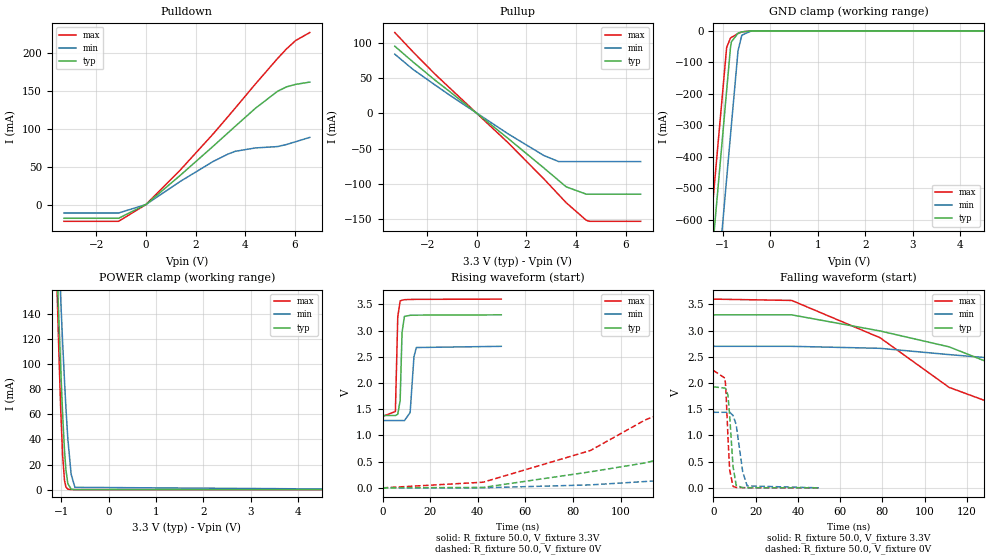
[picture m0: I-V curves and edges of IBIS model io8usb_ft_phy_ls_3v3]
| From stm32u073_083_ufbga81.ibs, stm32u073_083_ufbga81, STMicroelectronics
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[Model]   io8usb_ft_phy_ls_3v3
Model_type I/O
Polarity   Inverting
Enable   Active-Low
| CAP_THRESHOLD on pad DNFT is "UDTCAPC" :
| Rising=30.0% of vddiom   Falling=70.0% of vddiom
| C_comp min and max val. don't necessarily correlate with the min and max pvt
| but are the smallest and greatest pad capacitance found.
| var   typ   min   max
C_comp   8.83670pF  8.38806pF  11.45830pF
|C_comp_pullup   5.20650pF  4.52075pF  7.78905pF
|C_comp_pulldown   3.63020pF  3.86731pF  3.66925pF
Vinl = 810.0mV
Vinh = 2.52V
Vmeas = 1.65V   | Reference voltage for timing measurements
Cref  = 0F   | Timing specification test load capacitance value
Rref  = 100.0MOhm   | Timing specification test load resistance value
Vref  = 1.65V   | Timing specification test load voltage
[Model Spec]
| TIME_THRESHOLD on pin ZINV12 is "CMOS" :
| Rising=50.0% of vdd   Falling=50.0% of vdd
Vinl 1.34770V 1.11470V 1.44970V
Vinh 1.77530V 1.49030V 1.90330V
| variable   typ   min   max
[Temperature Range] 25.0 140.0 -40.0
| variable   typ   min   max
[Voltage Range] 3.3V 2.7V 3.6V
| variable   typ   min   max
[POWER Clamp Reference] 3.3V 2.7V 3.6V
| variable   typ   min   max
[GND Clamp Reference] 0V 0V 0V
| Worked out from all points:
|   slope of the pulldown table from 0 to 0.495 V, typ, clamps not added: 36.1 ohm
|   slope of the pullup table from 0 to 0.495 V, typ, clamps not added: 35.7 ohm
|   GND clamp passes 1 mA (typ) near -0.52 V on its own axis
|   POWER clamp passes 1 mA (typ) near -0.81 V on its own axis
|   rising waveform, R_fixture 50.0, V_fixture 3.3V: 20-80 % time 683ps typ, 1.12ns min, 579ps max; typ from 1.38 V to 3.3 V
|   falling waveform, R_fixture 50.0, V_fixture 3.3V: 20-80 % time 86ns typ, 163ns min, 57.1ns max; typ from 3.3 V to 1.38 V
|   rising waveform, R_fixture 50.0, V_fixture 0V: 20-80 % time 101ns typ, 204ns min, 66.9ns max; typ from 0 V to 1.93 V
|   falling waveform, R_fixture 50.0, V_fixture 0V: 20-80 % time 1.9ns typ, 2.98ns min, 1.51ns max; typ from 1.93 V to 0.001 V
[POWER Clamp]
-3.3V     2.991A     2.546A     3.694A
-1.11V    202.2mA    242.3mA    190.9mA
-1.09V    180mA      223.6mA    163.4mA
-1.05V    136.9mA    187mA      110.9mA
-1.01V    96.55mA    151.6mA    64.02mA
-970mV    60.39mA    117.9mA    27.41mA
-930mV    31.08mA    86.54mA    7.282mA
-900mV    15.67mA    65.13mA    2.025mA
-860mV    4.779mA    40.5mA     315.2uA
-790mV    394.2uA    12.22mA    11.25uA
-710mV    19.95uA    1.811mA    247.1nA
6.6V      0A         0A         0A
[GND Clamp]
-3.3V     -4.235A    -4.516A    -4.096A
-1.39V    -988.3mA   -1.268A    -848.9mA
-1.24V    -733.3mA   -1.014A    -593.9mA
-1.23V    -716.3mA   -996.5mA   -576.9mA
-1.1V     -495.3mA   -775.5mA   -355.9mA
-920mV    -189.3mA   -469.5mA   -53.02mA
-840mV    -54.5mA    -333.5mA   -23.28mA
-820mV    -35.01mA   -299.5mA   -20.98mA
-680mV    -7.53mA    -63.11mA   -8.471mA
-600mV    -3.376mA   -13.82mA   -3.494mA
-400mV    -43.64uA   -366.2uA   -14.84uA
6.6V      2.843nA    1.369uA    2.06nA
| variable   typ   min   max
[Pullup Reference] 3.3V 2.7V 3.6V
| variable   typ   min   max
[Pulldown Reference] 0V 0V 0V
[Pullup]
-3.3V     95.3mA     84mA       114.7mA
-2.58V    73.4mA     62.8mA     87.8mA
-1.7V     47.78mA    40.88mA    56.4mA
-1.1V     31.32mA    26.19mA    36.51mA
1.26V     -35.34mA   -28.86mA   -41.44mA
2.7V      -77.2mA    -59.59mA   -92.67mA
3.3V      -95.05mA   -68.22mA   -115.2mA
3.6V      -104mA     -68.22mA   -126.5mA
4.41V     -114.4mA   -68.22mA   -151.4mA
4.53V     -114.4mA   -68.22mA   -152.9mA
6.6V      -114.4mA   -68.22mA   -152.9mA
[Pulldown]
-3.3V     -18.08mA   -11.15mA   -22.07mA
-1.1V     -18.08mA   -11.15mA   -22.07mA
0V        431.7pA    53.17nA    569.2pA
1.38V     38.37mA    30.35mA    45.33mA
2.7V      76.5mA     56.57mA    92.67mA
3.31V     94.54mA    66.48mA    115.9mA
3.6V      103.1mA    70.09mA    127.1mA
4.41V     126.7mA    74.52mA    158.7mA
5.3V      149.1mA    76.3mA     192.2mA
5.66V     154.9mA    79mA       204.8mA
6.03V     158.2mA    82.7mA     215.9mA
6.6V      161.2mA    88.4mA     226.4mA
[Ramp]
dV/dt_r 1.15643V/99.05322ns 864.90818mV/195.52884ns 1.34448V/65.31321ns
dV/dt_f 1.15176V/83.79515ns 849.58363mV/160.14336ns 1.34245V/55.96383ns
R_load = 50.0
| Removed startup time: 0s 0s 0s  .
| Removed end time: 49.9ns.
[Rising Waveform]
R_fixture   = 50.0
V_fixture   = 3.3V
V_fixture_min = 2.7V
V_fixture_max = 3.6V
0s        1.38V      1.284V     1.363V
5.4ns     1.38V      1.284V     1.455V
6.4ns     1.403V     1.284V     3.26V
7.4ns     1.667V     1.284V     3.566V
8.2ns     2.964V     1.284V     3.579V
9.2ns     3.269V     1.283V     3.588V
11.6ns    3.291V     1.437V     3.593V
13.2ns    3.293V     2.499V     3.594V
14.2ns    3.294V     2.676V     3.595V
49.9ns    3.299V     2.699V     3.599V
| Removed startup time: 0s 0s 0s  .
| Removed end time: 999.9ns.
[Falling Waveform]
R_fixture   = 50.0
V_fixture   = 3.3V
V_fixture_min = 2.7V
V_fixture_max = 3.6V
0s        3.3V       2.7V       3.6V
37.1ns    3.3V       2.7V       3.575V
78.9ns    2.993V     2.662V     2.864V
111.6ns   2.69V      2.542V     1.917V
136.2ns   2.299V     2.461V     1.552V
165.3ns   1.829V     2.359V     1.388V
237.1ns   1.418V     1.995V     1.363V
333.3ns   1.381V     1.474V     1.363V
444.4ns   1.38V      1.301V     1.363V
999.9ns   1.38V      1.284V     1.363V
| Removed startup time: 0s 0s 0s  .
| Removed end time: 999.9ns.
[Rising Waveform]
R_fixture   = 50.0
V_fixture   = 0V
V_fixture_min = 0V
V_fixture_max = 0V
0s        84.75nV    591nV      53.04nV
42.3ns    8.46mV     1.182mV    107.9mV
87.4ns    306.3mV    56.56mV    713.3mV
110.1ns   474.4mV    120.1mV    1.289V
144.7ns   848.2mV    215.8mV    1.929V
192.5ns   1.499V     356.1mV    2.215V
276.9ns   1.888V     718mV      2.241V
348.5ns   1.926V     1.08V      2.241V
444.4ns   1.927V     1.338V     2.241V
999.9ns   1.927V     1.442V     2.241V
| Removed startup time: 0s 0s 0s  .
| Removed end time: 49.9ns.
[Falling Waveform]
R_fixture   = 50.0
V_fixture   = 0V
V_fixture_min = 0V
V_fixture_max = 0V
0s        1.927V     1.442V     2.241V
5.5ns     1.904V     1.442V     2.093V
5.9ns     1.883V     1.442V     1.901V
6.9ns     1.77V      1.443V     973.2mV
7.7ns     1.39V      1.443V     350.3mV
9.3ns     412.7mV    1.383V     28.97mV
10.8ns    48.64mV    1.206V     8.165mV
13.9ns    5.159mV    305.4mV    4.551mV
16ns      3.837mV    38.03mV    3.809mV
49.9ns    1.105mV    1.75mV     1.384mV
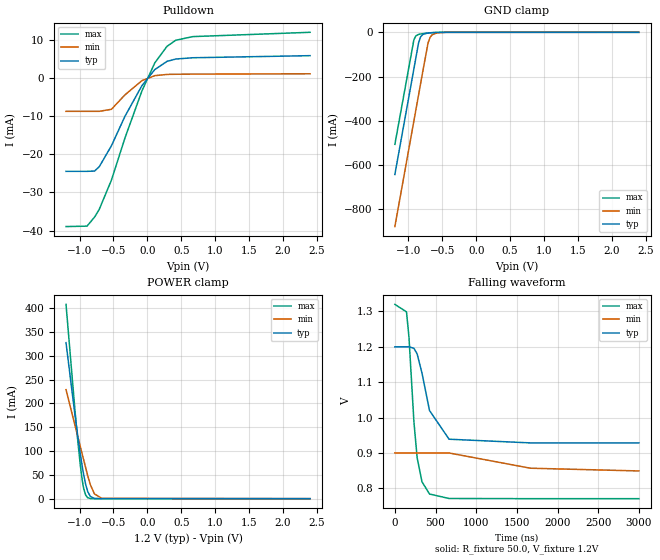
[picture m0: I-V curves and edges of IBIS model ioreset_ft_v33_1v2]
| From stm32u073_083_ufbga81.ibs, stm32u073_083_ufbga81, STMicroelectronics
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[Model]   ioreset_ft_v33_1v2
Model_type I/O_open_drain
Polarity   Inverting
Enable   Active-Low
| CAP_THRESHOLD on pad IOFT is "UDTCAPC" :
| Rising=30.0% of vddiom   Falling=70.0% of vddiom
| C_comp min and max val. don't necessarily correlate with the min and max pvt
| but are the smallest and greatest pad capacitance found.
| var   typ   min   max
C_comp   1.54805pF  1.41325pF  1.57330pF
|C_comp_pulldown   1.54805pF  1.41325pF  1.57330pF
Vinl = 450.0mV
Vinh = 660.0mV
Vmeas = 600.0mV   | Reference voltage for timing measurements
Cref  = 50.0pF   | Timing specification test load capacitance value
Rref  = 1.0MOhm   | Timing specification test load resistance value
Vref  = 660.0mV   | Timing specification test load voltage
[Model Spec]
| TIME_THRESHOLD on pin ZIV33M is "CMOS" :
| Rising=50.0% of vddiom   Falling=50.0% of vddiom
Vinl 458.70000mV 361.70000mV 499.70000mV
Vinh 728.30000mV 549.30000mV 792.30000mV
| variable   typ   min   max
[Temperature Range] 25.0 125.0 -40.0
| variable   typ   min   max
[Voltage Range] 1.2V 900.0mV 1.32V
| variable   typ   min   max
[POWER Clamp Reference] 1.2V 900.0mV 1.32V
| variable   typ   min   max
[GND Clamp Reference] 0V 0V 0V
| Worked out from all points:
|   slope of the pulldown table from 0 to 0.18 V, typ, clamps not added: 55.6 ohm
|   GND clamp passes 1 mA (typ) near -0.61 V on its own axis
|   POWER clamp passes 1 mA (typ) near -0.80 V on its own axis
|   falling waveform, R_fixture 50.0, V_fixture 1.2V: 20-80 % time 190ns typ, 488ns min, 98.8ns max; typ from 1.2 V to 0.928 V
[POWER Clamp]
-1.2V     327.4mA    228.8mA    407.7mA
-1.07V    177.7mA    155.3mA    188.5mA
-1.03V    134.8mA    132.7mA    126.3mA
-990mV    94.58mA    110.1mA    71.25mA
-960mV    67.13mA    93.17mA    38.08mA
-940mV    50.68mA    81.87mA    21.78mA
-910mV    29.83mA    64.92mA    7.377mA
-880mV    14.86mA    48.18mA    2.007mA
-840mV    4.466mA    28.97mA    309.8uA
-780mV    528.8uA    9.884mA    17.79uA
-670mV    8.746uA    604.9uA    93.27nA
2.4V      0A         0A         0A
[GND Clamp]
-1.2V     -642.1mA   -877.4mA   -506mA
-920mV    -166.1mA   -401.4mA   -34.33mA
-890mV    -115.1mA   -350.4mA   -16.11mA
-850mV    -47.11mA   -282.4mA   -9.454mA
-820mV    -19.89mA   -231.4mA   -7.573mA
-780mV    -8.064mA   -163.4mA   -5.871mA
-710mV    -3.141mA   -47.65mA   -3.479mA
-680mV    -2.306mA   -22.74mA   -2.619mA
-650mV    -1.672mA   -11.32mA   -1.871mA
-580mV    -657uA     -2.599mA   -639.7uA
-450mV    -34.01uA   -164.8uA   -16.77uA
2.4V      147.9pA    4.219nA    135.3pA
| variable   typ   min   max
[Pullup Reference] 1.2V 900.0mV 1.32V
| variable   typ   min   max
[Pulldown Reference] 0V 0V 0V
[Pulldown]
-1.2V     -24.47mA   -8.75mA    -38.94mA
-890mV    -24.47mA   -8.75mA    -38.83mA
-780mV    -24.4mA    -8.75mA    -36.48mA
-710mV    -23.27mA   -8.75mA    -34.44mA
-530mV    -17.77mA   -8.214mA   -26.77mA
-330mV    -10.03mA   -4.427mA   -15.71mA
-80mV     -2.009mA   -705.4uA   -3.396mA
110mV     2.198mA    601.5uA    3.95mA
290mV     4.348mA    923.6uA    8.288mA
420mV     4.961mA    964.2uA    9.88mA
670mV     5.29mA     1.001mA    10.83mA
2.4V      5.84mA     1.093mA    11.96mA
[Ramp]
dV/dt_r 162.87108mV/7.92487ns 30.59353mV/38.71206ns 329.5731mV/3.95351ns
dV/dt_f 162.93101mV/164.99055ns 30.54907mV/470.34313ns 329.57309mV/98.83445ns
R_load = 50.0
| Removed startup time: 0s 0s 0s  .
| Removed end time: 2.9998us.
[Falling Waveform]
R_fixture   = 50.0
V_fixture   = 1.2V
V_fixture_min = 900.0mV
V_fixture_max = 1.32V
0s        1.2V       900mV      1.32V
142.8ns   1.2V       900mV      1.299V
173.2ns   1.2V       900mV      1.228V
234ns     1.196V     900mV      988.9mV
274ns     1.18V      900mV      886.2mV
333.4ns   1.126V     900mV      818.6mV
425.8ns   1.02V      900mV      783.8mV
666.6ns   938.8mV    899.9mV    771.2mV
1.667us   928.4mV    856.8mV    770.7mV
3us       928.4mV    849.1mV    770.7mV
